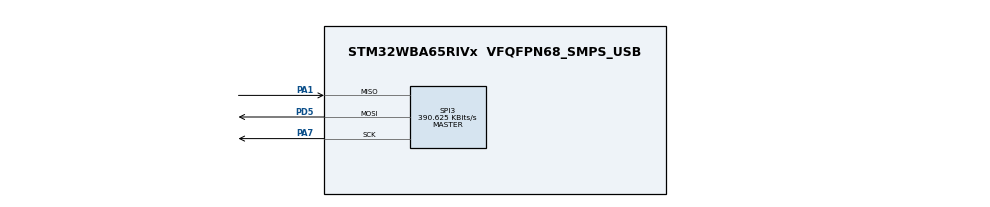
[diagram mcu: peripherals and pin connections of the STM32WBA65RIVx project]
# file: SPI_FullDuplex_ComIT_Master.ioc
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CORTEX_M33_NS.userName=CORTEX_M33
Mcu.Family=STM32WBA
Mcu.Name=STM32WBA65RIVx
Mcu.Package=VFQFPN68_SMPS_USB
NVIC.PriorityGroup=NVIC_PRIORITYGROUP_4
NVIC.SPI3_IRQn=true\:0\:0\:false\:false\:true\:true\:true\:true
OSC_IN.Mode=HSE-External-Oscillator
OSC_IN.PinAttribute=CortexM33
OSC_IN.Signal=RCC_OSC_IN
OSC_OUT.Mode=HSE-External-Oscillator
OSC_OUT.PinAttribute=CortexM33
OSC_OUT.Signal=RCC_OSC_OUT
PA1.Mode=Full_Duplex_Master
PA1.PinAttribute=CortexM33
PA1.Signal=SPI3_MISO
PA7.Mode=Full_Duplex_Master
PA7.PinAttribute=CortexM33
PA7.Signal=SPI3_SCK
PD5.GPIO_PuPd=GPIO_NOPULL
PD5.Mode=Full_Duplex_Master
PD5.PinAttribute=CortexM33
PD5.Signal=SPI3_MOSI
ProjectManager.HeapSize=0x200
ProjectManager.StackSize=0x400
ProjectManager.TargetToolchain=EWARM V9.20
RCC.ADCFreq_Value=100000000
RCC.AHB5CLKDivider=DIV4
RCC.AHBFreq_Value=100000000
RCC.APB1Freq_Value=100000000
RCC.APB1TimFreq_Value=100000000
RCC.APB2Freq_Value=100000000
RCC.APB2TimFreq_Value=100000000
RCC.CortexFreq_Value=12500000
RCC.HCLKFreq_Value=100000000
RCC.HSE_VALUE=32000000
RCC.HSI_VALUE=16000000
RCC.LSE_VALUE=32768
RCC.LSI1_VALUE=32000
RCC.LSI2_VALUE=32000
RCC.PLLFRACN=4096
RCC.PLLM=2
RCC.PLLN=12
RCC.PLLSourceVirtual=RCC_PLLSOURCE_HSE
RCC.SYSCLKFreq_VALUE=100000000
RCC.SYSCLKSourceVirtual=RCC_SYSCLKSOURCE_PLLCLK
RCC.VCOOutputFreq_Value=200000000
SPI3.BaudRatePrescaler=SPI_BAUDRATEPRESCALER_256
SPI3.CLKPhase=SPI_PHASE_1EDGE
SPI3.CLKPolarity=SPI_POLARITY_LOW
SPI3.CRCCalculation=SPI_CRCCALCULATION_DISABLE
SPI3.CalculateBaudRate=390.625 KBits/s
SPI3.DataSize=SPI_DATASIZE_8BIT
SPI3.Direction=SPI_DIRECTION_2LINES
SPI3.FirstBit=SPI_FIRSTBIT_MSB
SPI3.GPIO_SPEED=GPIO_SPEED_FREQ_VERY_HIGH
SPI3.Mode=SPI_MODE_MASTER
SPI3.NSS=SPI_NSS_SOFT
SPI3.NSSPMode=SPI_NSS_PULSE_DISABLE
SPI3.TIMode=SPI_TIMODE_DISABLE
SPI3.VirtualType=VM_MASTER
VP_CORTEX_M33_NS_VS_Hclk.Mode=Hclk_Mode
VP_ICACHE_VS_ICACHE.Mode=DirectMappedCache
VP_PWR_VS_SECSignals.Mode=Security/Privilege
board=custom

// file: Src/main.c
/* USER CODE BEGIN Header */
/**
  ******************************************************************************
  * @file    SPI/SPI_FullDuplex_ComIT_Master/Src/main.c
  * @author  MCD Application Team
  * @brief   This sample code shows how to use STM32WBAxx SPI HAL API to transmit
  *          and receive a data buffer with a communication process based on
  *          Interrupt transfer.
  *          The communication is done using 2 Boards.
  ******************************************************************************

  * @attention
  *
  * Copyright (c) 2023 STMicroelectronics.
  * All rights reserved.
  *
  * This software is licensed under terms that can be found in the LICENSE fil
  * in the root directory of this software component.
  * If no LICENSE file comes with this software, it is provided AS-IS.
  *
  ******************************************************************************
  */
/* USER CODE END Header */
#include "main.h"

/* USER CODE BEGIN PD */
enum
{
  TRANSFER_WAIT,
  TRANSFER_COMPLETE,
  TRANSFER_ERROR
};
/* USER CODE END PD */

SPI_HandleTypeDef hspi3;

/* USER CODE BEGIN PV */
/* Buffer used for transmission */
uint8_t aTxBuffer[] = "****SPI - Two Boards communication based on Interrupt **** SPI Message ******** SPI Message ******** SPI Message ****";

/* Buffer used for reception */
uint8_t aRxBuffer[BUFFERSIZE];

/* transfer state */
__IO uint32_t wTransferState = TRANSFER_WAIT;

__IO uint8_t    ubUserButtonClickEvent = RESET;  /* Event detection: Set after User Button interrupt */
/* USER CODE END PV */

void SystemClock_Config(void);
static void MX_GPIO_Init(void);
static void MX_SPI3_Init(void);
static void MX_ICACHE_Init(void);
/* USER CODE BEGIN PFP */
static uint16_t Buffercmp(uint8_t *pBuffer1, uint8_t *pBuffer2, uint16_t BufferLength);
/* USER CODE END PFP */

int main(void)
{

  /* USER CODE BEGIN 1 */

  /* STM32WBAxx HAL library initialization:
       - Systick timer is configured by default as source of time base, but user
             can eventually implement his proper time base source (a general purpose
             timer for example or other time source), keeping in mind that Time base
             duration should be kept 1ms since PPP_TIMEOUT_VALUEs are defined and
             handled in milliseconds basis.
       - Set NVIC Group Priority to 4
       - Low Level Initialization
     */
  /* USER CODE END 1 */

  /* MCU Configuration--------------------------------------------------------*/

  /* Reset of all peripherals, Initializes the Flash interface and the Systick. */
  HAL_Init();

  /* Configure the system clock */
  SystemClock_Config();

  /* Initialize all configured peripherals */
  MX_GPIO_Init();
  MX_SPI3_Init();
  MX_ICACHE_Init();
  /* USER CODE BEGIN 2 */

  /* Configure LD1, LD2 and LD3 */
  BSP_LED_Init(LD1);
  BSP_LED_Init(LD2);
  BSP_LED_Init(LD3);

  /* Configure USER push-button button */
  BSP_PB_Init(B1, BUTTON_MODE_EXTI);

  /* Wait for event on push button to perform following actions */
  while ((ubUserButtonClickEvent) == RESET)
  {
    BSP_LED_Toggle(LD1);
    HAL_Delay(100);
  }

  BSP_LED_Off(LD1);

  /*##-1- Start the Full Duplex Communication process ########################*/
  /* While the SPI in TransmitReceive process, user can transmit data through
     "aTxBuffer" buffer & receive data through "aRxBuffer" */
  if (HAL_SPI_TransmitReceive_IT(&hspi3, (uint8_t *)aTxBuffer, (uint8_t *)aRxBuffer, BUFFERSIZE) != HAL_OK)
  {
    /* Transfer error in transmission process */
    Error_Handler();
  }

  /*##-2- Wait for the end of the transfer ###################################*/
  /*  Before starting a new communication transfer, you must wait the callback call
      to get the transfer complete confirmation or an error detection.
      For simplicity reasons, this example is just waiting till the end of the
      transfer, but application may perform other tasks while transfer operation
      is ongoing. */
  while (wTransferState == TRANSFER_WAIT)
  {
  }

  switch (wTransferState)
  {
    case TRANSFER_COMPLETE :
      /*##-3- Compare the sent and received buffers ##############################*/
      if (Buffercmp((uint8_t *)aTxBuffer, (uint8_t *)aRxBuffer, BUFFERSIZE))
      {
        /* Processing Error */
        Error_Handler();
      }
      break;
    default :
      Error_Handler();
      break;
  }

  /* USER CODE END 2 */

  /* Infinite loop */
  while (1)
  {

  }
}

void SystemClock_Config(void)
{
  RCC_OscInitTypeDef RCC_OscInitStruct = {0};
  RCC_ClkInitTypeDef RCC_ClkInitStruct = {0};

  /** Supply configuration update enable
  */
  HAL_PWREx_ConfigSupply(PWR_LDO_SUPPLY);

  /** Configure the main internal regulator output voltage
  */
  if (HAL_PWREx_ControlVoltageScaling(PWR_REGULATOR_VOLTAGE_SCALE1) != HAL_OK)
  {
    Error_Handler();
  }

  /** Initializes the CPU, AHB and APB busses clocks
  */
  RCC_OscInitStruct.OscillatorType = RCC_OSCILLATORTYPE_HSE;
  RCC_OscInitStruct.HSEState = RCC_HSE_ON;
  RCC_OscInitStruct.HSEDiv = RCC_HSE_DIV1;
  RCC_OscInitStruct.PLL1.PLLState = RCC_PLL_ON;
  RCC_OscInitStruct.PLL1.PLLSource = RCC_PLLSOURCE_HSE;
  RCC_OscInitStruct.PLL1.PLLM = 2;
  RCC_OscInitStruct.PLL1.PLLN = 12;
  RCC_OscInitStruct.PLL1.PLLP = 2;
  RCC_OscInitStruct.PLL1.PLLQ = 2;
  RCC_OscInitStruct.PLL1.PLLR = 2;
  RCC_OscInitStruct.PLL1.PLLFractional = 4096;
  if (HAL_RCC_OscConfig(&RCC_OscInitStruct) != HAL_OK)
  {
    Error_Handler();
  }

  /** Initializes the CPU, AHB and APB busses clocks
  */
  RCC_ClkInitStruct.ClockType = RCC_CLOCKTYPE_HCLK|RCC_CLOCKTYPE_SYSCLK
                              |RCC_CLOCKTYPE_PCLK1|RCC_CLOCKTYPE_PCLK2
                              |RCC_CLOCKTYPE_PCLK7|RCC_CLOCKTYPE_HCLK5;
  RCC_ClkInitStruct.SYSCLKSource = RCC_SYSCLKSOURCE_PLLCLK;
  RCC_ClkInitStruct.AHBCLKDivider = RCC_SYSCLK_DIV1;
  RCC_ClkInitStruct.APB1CLKDivider = RCC_HCLK_DIV1;
  RCC_ClkInitStruct.APB2CLKDivider = RCC_HCLK_DIV1;
  RCC_ClkInitStruct.APB7CLKDivider = RCC_HCLK_DIV1;
  RCC_ClkInitStruct.AHB5_PLL1_CLKDivider = RCC_SYSCLK_PLL1_DIV4;
  RCC_ClkInitStruct.AHB5_HSEHSI_CLKDivider = RCC_SYSCLK_HSEHSI_DIV1;

  if (HAL_RCC_ClockConfig(&RCC_ClkInitStruct, FLASH_LATENCY_3) != HAL_OK)
  {
    Error_Handler();
  }
}

static void MX_ICACHE_Init(void)
{

  /** Enable instruction cache in 1-way (direct mapped cache)
  */
  if (HAL_ICACHE_ConfigAssociativityMode(ICACHE_1WAY) != HAL_OK)
  {
    Error_Handler();
  }
  if (HAL_ICACHE_Enable() != HAL_OK)
  {
    Error_Handler();
  }

}

static void MX_SPI3_Init(void)
{

  /* SPI3 parameter configuration*/
  hspi3.Instance = SPI3;
  hspi3.Init.Mode = SPI_MODE_MASTER;
  hspi3.Init.Direction = SPI_DIRECTION_2LINES;
  hspi3.Init.DataSize = SPI_DATASIZE_8BIT;
  hspi3.Init.CLKPolarity = SPI_POLARITY_LOW;
  hspi3.Init.CLKPhase = SPI_PHASE_1EDGE;
  hspi3.Init.NSS = SPI_NSS_SOFT;
  hspi3.Init.BaudRatePrescaler = SPI_BAUDRATEPRESCALER_256;
  hspi3.Init.FirstBit = SPI_FIRSTBIT_MSB;
  hspi3.Init.TIMode = SPI_TIMODE_DISABLE;
  hspi3.Init.CRCCalculation = SPI_CRCCALCULATION_DISABLE;
  hspi3.Init.CRCPolynomial = 0x7;
  hspi3.Init.NSSPMode = SPI_NSS_PULSE_DISABLE;
  hspi3.Init.NSSPolarity = SPI_NSS_POLARITY_LOW;
  hspi3.Init.FifoThreshold = SPI_FIFO_THRESHOLD_01DATA;
  hspi3.Init.MasterSSIdleness = SPI_MASTER_SS_IDLENESS_00CYCLE;
  hspi3.Init.MasterInterDataIdleness = SPI_MASTER_INTERDATA_IDLENESS_00CYCLE;
  hspi3.Init.MasterReceiverAutoSusp = SPI_MASTER_RX_AUTOSUSP_DISABLE;
  hspi3.Init.MasterKeepIOState = SPI_MASTER_KEEP_IO_STATE_DISABLE;
  hspi3.Init.IOSwap = SPI_IO_SWAP_DISABLE;
  hspi3.Init.ReadyMasterManagement = SPI_RDY_MASTER_MANAGEMENT_INTERNALLY;
  hspi3.Init.ReadyPolarity = SPI_RDY_POLARITY_HIGH;
  if (HAL_SPI_Init(&hspi3) != HAL_OK)
  {
    Error_Handler();
  }

}

static void MX_GPIO_Init(void)
{

  /* GPIO Ports Clock Enable */
  __HAL_RCC_GPIOA_CLK_ENABLE();
  __HAL_RCC_GPIOD_CLK_ENABLE();

}

/* USER CODE BEGIN 4 */
/**
  * @brief  TxRx Transfer completed callback.
  * @param  hspi: SPI handle
  * @note   This example shows a simple way to report end of Interrupt TxRx transfer, and
  *         you can add your own implementation.
  * @retval None
  */
void HAL_SPI_TxRxCpltCallback(SPI_HandleTypeDef *hspi)
{
  /* Turn LD1 on: Transfer in transmission process is complete */
  BSP_LED_On(LD1);
  /* Turn LD2 on: Transfer in reception process is complete */
  BSP_LED_On(LD2);
  wTransferState = TRANSFER_COMPLETE;
}

/**
  * @brief  SPI error callbacks.
  * @param  hspi: SPI handle
  * @note   This example shows a simple way to report transfer error, and you can
  *         add your own implementation.
  * @retval None
  */
void HAL_SPI_ErrorCallback(SPI_HandleTypeDef *hspi)
{
  wTransferState = TRANSFER_ERROR;
}

/**
  * @brief  Compares two buffers.
  * @param  pBuffer1, pBuffer2: buffers to be compared.
  * @param  BufferLength: buffer's length
  * @retval 0  : pBuffer1 identical to pBuffer2
  *         >0 : pBuffer1 differs from pBuffer2
  */
static uint16_t Buffercmp(uint8_t *pBuffer1, uint8_t *pBuffer2, uint16_t BufferLength)
{
  while (BufferLength--)
  {
    if ((*pBuffer1) != *pBuffer2)
    {
      return BufferLength;
    }
    pBuffer1++;
    pBuffer2++;
  }

  return 0;
}

/**
  * @brief EXTI line detection callbacks
  * @param  GPIO_Pin Specifies the port pin connected to corresponding EXTI line.
  * @retval None
  */
void HAL_GPIO_EXTI_Falling_Callback(uint16_t GPIO_Pin)
{
  if (GPIO_Pin == B1_PIN)
  {
    /* Set variable to report push button event to main program */
    ubUserButtonClickEvent = SET;
  }
}

/* USER CODE END 4 */

void Error_Handler(void)
{
  /* USER CODE BEGIN Error_Handler_Debug */
  /* User can add his own implementation to report the HAL error return state */
  /* Turn LD3 on */
  BSP_LED_On(LD3);
  while (1)
  {
  }
  /* USER CODE END Error_Handler_Debug */
}
